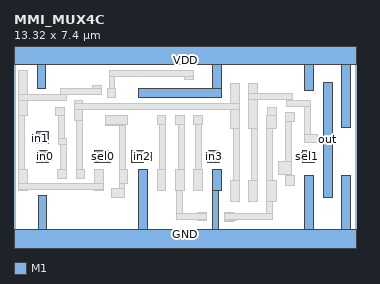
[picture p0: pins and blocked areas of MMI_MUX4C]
MACRO MMI_MUX4C
	CLASS CORE ;
	FOREIGN MMI_MUX4C 0 0 ;
	SIZE 13.32 BY 7.4 ;
	SYMMETRY X Y ;
	SITE CORE1 ;
	PIN out
		DIRECTION output ;
		USE SIGNAL ;
		PORT
			LAYER M1 ;
			RECT 12.05 1.75 12.39 6.225 ;
		END
		AntennaDiffArea 1.4904 ;
	END out
	PIN sel0
		DIRECTION input ;
		USE SIGNAL ;
		PORT
			LAYER M1 ;
			RECT 3.15 3.095 3.75 3.56 ;
		END
		AntennaGateArea 1.3284 ;
	END sel0
	PIN in1
		DIRECTION input ;
		USE SIGNAL ;
		PORT
			LAYER M1 ;
			RECT 0.885 4.205 1.335 4.295 ;
			LAYER M1 ;
			RECT 0.66 3.865 1.335 4.205 ;
			LAYER M1 ;
			RECT 0.885 3.845 1.335 3.865 ;
		END
		AntennaGateArea 0.4968 ;
	END in1
	PIN GND
		DIRECTION inout ;
		USE GROUND ;
		PORT
			LAYER M1 ;
			RECT 0.94 0.5 1.28 1.8 ;
			LAYER M1 ;
			RECT 4.85 0.5 5.19 2.83 ;
			LAYER M1 ;
			RECT 7.73 1.99 8.07 2.83 ;
			LAYER M1 ;
			RECT 7.73 0.5 7.96 1.99 ;
			LAYER M1 ;
			RECT 11.33 0.5 11.67 2.59 ;
			LAYER M1 ;
			RECT 12.77 0.5 13.11 2.59 ;
			LAYER M1 ;
			RECT 0 -0.5 13.32 0.5 ;
		END
	END GND
	PIN in2
		DIRECTION input ;
		USE SIGNAL ;
		PORT
			LAYER M1 ;
			RECT 4.585 3.5 5.035 3.555 ;
			LAYER M1 ;
			RECT 4.585 3.16 5.35 3.5 ;
			LAYER M1 ;
			RECT 4.585 3.105 5.035 3.16 ;
		END
		AntennaGateArea 0.4968 ;
	END in2
	PIN sel1
		DIRECTION input ;
		USE SIGNAL ;
		PORT
			LAYER M1 ;
			RECT 11.245 3.5 11.695 3.555 ;
			LAYER M1 ;
			RECT 11.1 3.16 11.695 3.5 ;
			LAYER M1 ;
			RECT 11.245 3.105 11.695 3.16 ;
		END
		AntennaGateArea 0.7452 ;
	END sel1
	PIN VDD
		DIRECTION inout ;
		USE POWER ;
		PORT
			LAYER M1 ;
			RECT 0 6.9 13.32 7.9 ;
			LAYER M1 ;
			RECT 0.9 5.995 1.24 6.9 ;
			LAYER M1 ;
			RECT 7.73 5.965 8.07 6.9 ;
			LAYER M1 ;
			RECT 4.85 5.625 8.07 5.965 ;
			LAYER M1 ;
			RECT 11.33 5.885 11.67 6.9 ;
			LAYER M1 ;
			RECT 12.77 4.465 13.11 6.9 ;
		END
	END VDD
	PIN in3
		DIRECTION input ;
		USE SIGNAL ;
		PORT
			LAYER M1 ;
			RECT 7.545 3.5 7.995 3.555 ;
			LAYER M1 ;
			RECT 7.545 3.16 8.01 3.5 ;
			LAYER M1 ;
			RECT 7.545 3.105 7.995 3.16 ;
		END
		AntennaGateArea 0.4968 ;
	END in3
	PIN in0
		DIRECTION input ;
		USE SIGNAL ;
		PORT
			LAYER M1 ;
			RECT 0.885 3.5 1.335 3.555 ;
			LAYER M1 ;
			RECT 0.885 3.16 1.515 3.5 ;
			LAYER M1 ;
			RECT 0.885 3.105 1.335 3.16 ;
		END
		AntennaGateArea 0.4968 ;
	END in0
	OBS
		LAYER M1 ;
		RECT 0.18 5.735 0.52 6.67 ;
		LAYER M1 ;
		RECT 3.7 6.435 6.99 6.665 ;
		LAYER M1 ;
		RECT 3.06 5.99 3.4 6.1 ;
		LAYER M1 ;
		RECT 1.81 5.76 3.4 5.99 ;
		LAYER M1 ;
		RECT 3.7 5.96 3.93 6.435 ;
		LAYER M1 ;
		RECT 6.65 6.325 6.99 6.435 ;
		LAYER M1 ;
		RECT 1.81 5.735 2.04 5.76 ;
		LAYER M1 ;
		RECT 0.18 5.505 2.04 5.735 ;
		LAYER M1 ;
		RECT 3.63 5.62 3.97 5.96 ;
		LAYER M1 ;
		RECT 0.18 4.91 0.52 5.505 ;
		LAYER M1 ;
		RECT 2.34 5.39 2.68 5.53 ;
		LAYER M1 ;
		RECT 8.43 5.39 8.77 6.185 ;
		LAYER M1 ;
		RECT 1.62 4.91 1.96 5.25 ;
		LAYER M1 ;
		RECT 0.18 2.83 0.41 4.91 ;
		LAYER M1 ;
		RECT 1.73 4.02 1.96 4.91 ;
		LAYER M1 ;
		RECT 2.34 5.16 8.77 5.39 ;
		LAYER M1 ;
		RECT 2.34 4.72 2.68 5.16 ;
		LAYER M1 ;
		RECT 1.73 3.79 2.04 4.02 ;
		LAYER M1 ;
		RECT 1.81 2.83 2.04 3.79 ;
		LAYER M1 ;
		RECT 2.43 2.83 2.66 4.72 ;
		LAYER M1 ;
		RECT 3.565 4.585 4.43 4.925 ;
		LAYER M1 ;
		RECT 5.57 4.59 5.91 4.93 ;
		LAYER M1 ;
		RECT 6.29 4.59 6.63 4.93 ;
		LAYER M1 ;
		RECT 7.01 4.59 7.35 4.93 ;
		LAYER M1 ;
		RECT 3.565 4.555 4.35 4.585 ;
		LAYER M1 ;
		RECT 4.12 2.83 4.35 4.555 ;
		LAYER M1 ;
		RECT 5.68 2.83 5.91 4.59 ;
		LAYER M1 ;
		RECT 6.4 2.83 6.63 4.59 ;
		LAYER M1 ;
		RECT 7.085 2.83 7.315 4.59 ;
		LAYER M1 ;
		RECT 8.43 4.425 8.77 5.16 ;
		LAYER M1 ;
		RECT 9.15 5.765 9.49 6.185 ;
		LAYER M1 ;
		RECT 9.15 5.535 10.835 5.765 ;
		LAYER M1 ;
		RECT 9.15 4.425 9.49 5.535 ;
		LAYER M1 ;
		RECT 10.605 5.5 10.835 5.535 ;
		LAYER M1 ;
		RECT 10.605 5.27 11.53 5.5 ;
		LAYER M1 ;
		RECT 9.87 4.935 10.21 5.235 ;
		LAYER M1 ;
		RECT 0.18 2.26 0.52 2.83 ;
		LAYER M1 ;
		RECT 1.7 2.49 2.04 2.83 ;
		LAYER M1 ;
		RECT 2.42 2.49 2.76 2.83 ;
		LAYER M1 ;
		RECT 3.14 2.26 3.48 2.83 ;
		LAYER M1 ;
		RECT 0.18 2.03 3.48 2.26 ;
		LAYER M1 ;
		RECT 4.09 2.29 4.43 2.83 ;
		LAYER M1 ;
		RECT 4.09 2.085 4.32 2.29 ;
		LAYER M1 ;
		RECT 0.18 1.99 0.52 2.03 ;
		LAYER M1 ;
		RECT 3.14 1.99 3.48 2.03 ;
		LAYER M1 ;
		RECT 3.815 1.745 4.32 2.085 ;
		LAYER M1 ;
		RECT 5.57 1.99 5.91 2.83 ;
		LAYER M1 ;
		RECT 6.29 1.99 6.63 2.83 ;
		LAYER M1 ;
		RECT 7.01 1.99 7.35 2.83 ;
		LAYER M1 ;
		RECT 8.54 2.41 8.77 4.425 ;
		LAYER M1 ;
		RECT 9.26 2.41 9.49 4.425 ;
		LAYER M1 ;
		RECT 6.325 1.105 6.555 1.99 ;
		LAYER M1 ;
		RECT 7.145 1.105 7.485 1.16 ;
		LAYER M1 ;
		RECT 6.325 0.875 7.485 1.105 ;
		LAYER M1 ;
		RECT 7.145 0.82 7.485 0.875 ;
		LAYER M1 ;
		RECT 8.43 1.57 8.77 2.41 ;
		LAYER M1 ;
		RECT 9.15 1.57 9.49 2.41 ;
		LAYER M1 ;
		RECT 9.845 4.425 10.21 4.935 ;
		LAYER M1 ;
		RECT 10.57 4.7 10.91 5.04 ;
		LAYER M1 ;
		RECT 9.845 2.41 10.075 4.425 ;
		LAYER M1 ;
		RECT 10.57 3.13 10.8 4.7 ;
		LAYER M1 ;
		RECT 11.3 4.205 11.53 5.27 ;
		LAYER M1 ;
		RECT 11.3 3.865 11.82 4.205 ;
		LAYER M1 ;
		RECT 10.305 2.64 10.8 3.13 ;
		LAYER M1 ;
		RECT 10.57 2.59 10.8 2.64 ;
		LAYER M1 ;
		RECT 9.845 1.57 10.21 2.41 ;
		LAYER M1 ;
		RECT 10.57 2.21 10.91 2.59 ;
		LAYER M1 ;
		RECT 8.2 1.095 8.54 1.155 ;
		LAYER M1 ;
		RECT 9.845 1.095 10.075 1.57 ;
		LAYER M1 ;
		RECT 8.2 0.865 10.075 1.095 ;
		LAYER M1 ;
		RECT 8.2 0.855 8.655 0.865 ;
		LAYER M1 ;
		RECT 8.2 0.815 8.54 0.855 ;
	END
END MMI_MUX4C
